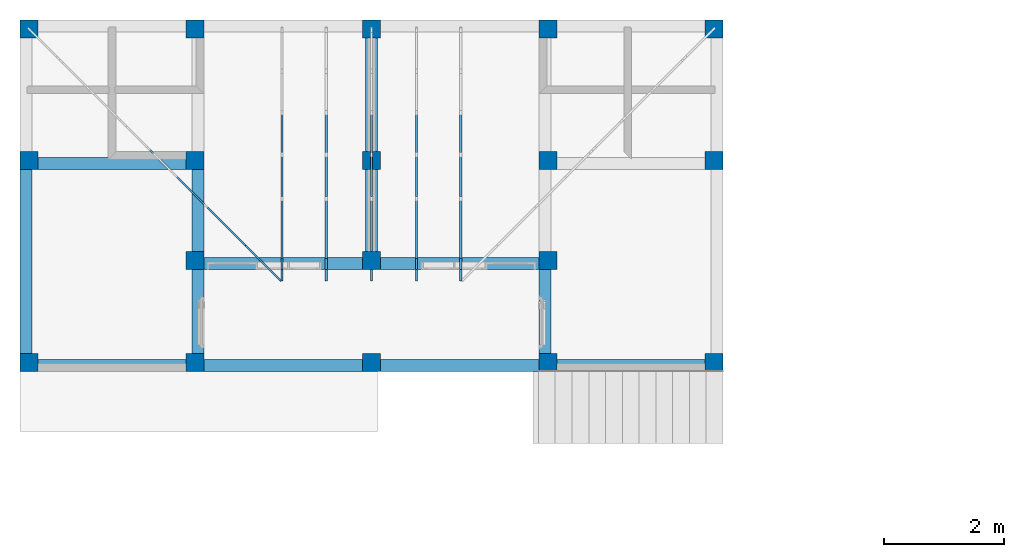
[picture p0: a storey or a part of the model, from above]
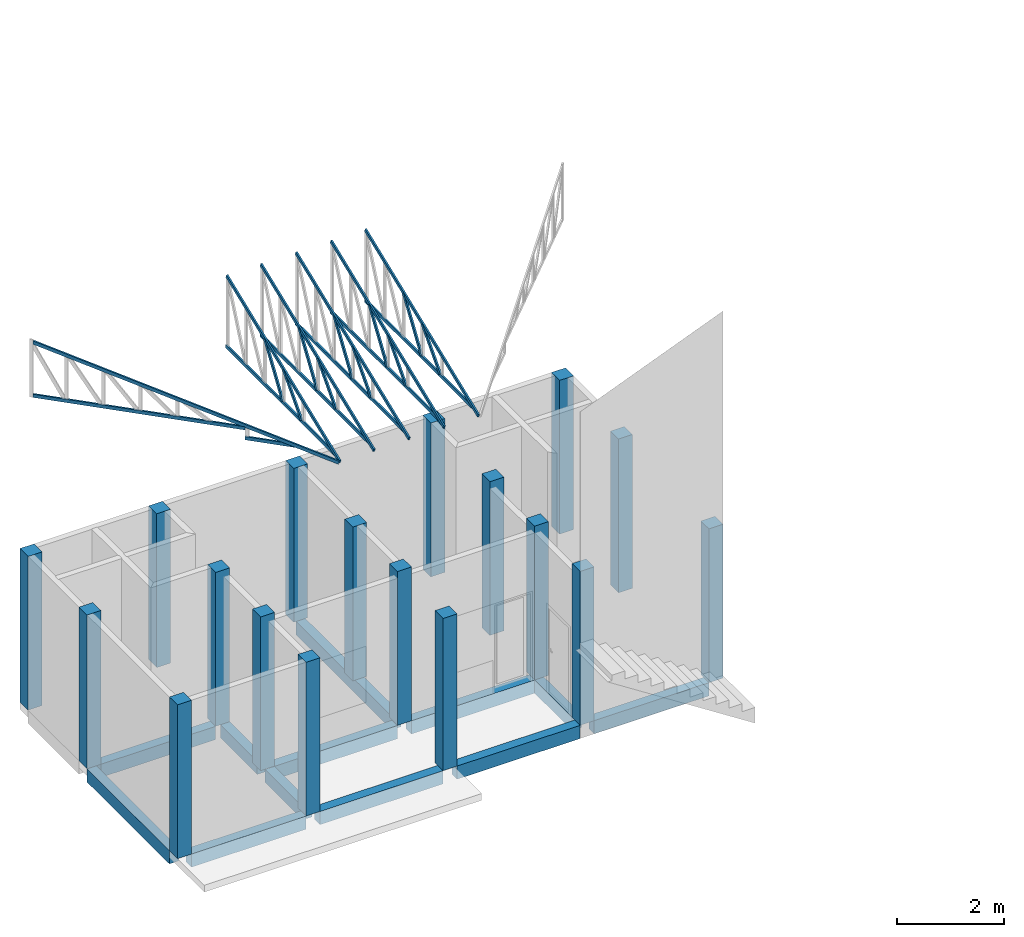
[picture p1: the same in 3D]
Properties of the parts of a building model (IFC4X3_ADD2)

# File
Description: ViewDefinition[DesignTransferView]
File name: kost-IFC4X3.ifc
Time: 2025-10-08T06:04:25+08:00
Written by: IfcOpenShell 0.8.4-alpha251007
Made in: Bonsai 0.8.4-alpha251007-bd0cfa5
Authorization: Nobody

# IfcProject, My Project
Document: BBIM_Cost_Documents; Beam; LANTAI 2 PLAN; UNTITLED; SOUTH ELEVATION; Beam LT2; ATAS PLAN; RANGKA ATAP; ORTHOGRAPHIC

# IfcAnnotation (11)
Group: LANTAI 1 PLAN
Name | PredefinedType
7 x DIMENSION | DIMENSION
4 x TEXT | TEXT | EPset_Annotation - Newline_At: 0; Reverse_List: no; List_Separator: ,

# IfcAnnotation: DRAWING (9)
PredefinedType: USERDEFINED
EPset_Drawing - HasUnderlay: no; HasLinework: yes; HasAnnotation: yes; GlobalReferencing: yes; Markers: drawings/assets/markers.svg; Symbols: drawings/assets/symbols.svg; Patterns: drawings/assets/patterns.svg; ShadingStyles: drawings/assets/shading_styles.json
Name | Document | TargetView | Scale | HumanScale | Stylesheet | CurrentShadingStyle | BringToFront | Group
LANTAI 1 PLAN | X drawings/Beam.svg | PLAN_VIEW | 1/100 | 1:100 | drawings/assets/default.css | Blender Default | IfcColumn | LANTAI 1 PLAN
LANTAI 2 PLAN | X drawings/LANTAI 2 PLAN.svg | PLAN_VIEW | 1/100 | 1:100 | drawings/assets/default.css | Blender Default | IfcColumn | LANTAI 2 PLAN
LANTAI 1 PLAN-X | X drawings/Beam.svg | PLAN_VIEW | 1/100 | 1:100 | drawings/assets/default.css | Blender Default | IfcColumn | LANTAI 1 PLAN-X
Beam | X drawings/Beam.svg | PLAN_VIEW | 1/100 | 1:100 | drawings/assets/Beam.css | Blender Default | IfcColumn | Beam | EPset_Drawing - Exclude: IfcWall, IfcDoor, IfcSlab
SOUTH ELEVATION | X drawings/SOUTH ELEVATION.svg | ELEVATION_VIEW | 1/100 | 1:100 | drawings/assets/default.css | Technical |  | SOUTH ELEVATION
Beam LT2 | X drawings/Beam LT2.svg | PLAN_VIEW | 1/100 | 1:100 | drawings/assets/default.css | Blender Default | IfcColumn | Beam LT2 | EPset_Drawing - Exclude: IfcElement, !IfcColumn, !IfcBeam
ATAS PLAN | X drawings/ATAS PLAN.svg | PLAN_VIEW | 1/100 | 1:100 | drawings/assets/default.css | Blender Default |  | ATAS PLAN
RANGKA ATAP | X drawings/RANGKA ATAP.svg | PLAN_VIEW | 1/50 | 1:50 | drawings/assets/default.css | Blender Default |  | RANGKA ATAP | EPset_Drawing - Exclude: IfcRoof, IfcWall, IfcDoor, IfcCovering
ORTHOGRAPHIC | X drawings/ORTHOGRAPHIC.svg | MODEL_VIEW | 1/100 | 1:100 | drawings/assets/default.css | Blender Default |  | ORTHOGRAPHIC

# IfcAnnotation: ELEVATION (6)
PredefinedType: USERDEFINED
Name | Group
IfcAnnotation/SOUTH ELEVATION | Beam
IfcAnnotation/SOUTH ELEVATION | LANTAI 2 PLAN
IfcAnnotation/SOUTH ELEVATION | Beam LT2
IfcAnnotation/SOUTH ELEVATION | ATAS PLAN
IfcAnnotation/SOUTH ELEVATION | RANGKA ATAP
IfcAnnotation/SOUTH ELEVATION | LANTAI 1 PLAN

# IfcAnnotation: GRID (105)
PredefinedType: USERDEFINED
Name | Group
4 x A | LANTAI 1 PLAN
2 x B | LANTAI 1 PLAN
D | LANTAI 1 PLAN
01 | LANTAI 1 PLAN
2 x 02 | LANTAI 1 PLAN
3 x 03 | LANTAI 1 PLAN
2 x 04 | LANTAI 1 PLAN
4 x 05 | LANTAI 1 PLAN
2 x A | LANTAI 2 PLAN
2 x B | LANTAI 2 PLAN
3 x C | LANTAI 2 PLAN
3 x 01 | LANTAI 2 PLAN
4 x 02 | LANTAI 2 PLAN
3 x 03 | LANTAI 2 PLAN
04 | LANTAI 2 PLAN
05 | LANTAI 2 PLAN
2 x C | LANTAI 1 PLAN
2 x A | Beam
B | Beam
2 x C | Beam
01 | Beam
02 | Beam
4 x 03 | Beam
04 | Beam
05 | Beam
4 x 03 | SOUTH ELEVATION
01 | SOUTH ELEVATION
02 | SOUTH ELEVATION
05 | SOUTH ELEVATION
2 x A | Beam LT2
B | Beam LT2
2 x C | Beam LT2
01 | Beam LT2
02 | Beam LT2
3 x 03 | Beam LT2
04 | Beam LT2
05 | Beam LT2
3 x C | ATAS PLAN
4 x 03 | ATAS PLAN
2 x A | ATAS PLAN
B | ATAS PLAN
01 | ATAS PLAN
02 | ATAS PLAN
04 | ATAS PLAN
05 | ATAS PLAN
2 x A | RANGKA ATAP
B | RANGKA ATAP
C | RANGKA ATAP
01 | RANGKA ATAP
02 | RANGKA ATAP
2 x 03 | RANGKA ATAP
04 | RANGKA ATAP
05 | RANGKA ATAP
04 | SOUTH ELEVATION
A | ORTHOGRAPHIC
B | ORTHOGRAPHIC
C | ORTHOGRAPHIC
01 | ORTHOGRAPHIC
02 | ORTHOGRAPHIC
03 | ORTHOGRAPHIC
04 | ORTHOGRAPHIC
05 | ORTHOGRAPHIC

# IfcAnnotation: SECTION_LEVEL (5)
PredefinedType: USERDEFINED; Group: SOUTH ELEVATION
Name
IfcBuildingStorey/Lantai 1
IfcBuildingStorey/Lantai 2
IfcBuildingStorey/Riang Blok
IfcBuildingStorey/Pondasi
IfcBuildingStorey/ATAS

# IfcBeam: RB (25)
In: Lantai 2
Type - PredefinedType: BEAM; Material: plester
EPset_Parametric - Engine: Bonsai.DumbProfile
Name | Group
5 x Beam
20 x Beam | TB_LT2

# IfcBeam: TB1 (52)
Type - PredefinedType: BEAM; Material: plester
EPset_Parametric - Engine: Bonsai.DumbProfile
Name | In
22 x Beam | Lantai 1
Beam | Lantai 1 | Group: TB_LT2
3 x Beam | Riang Blok
20 x Beam | Lantai 2 | Group: TB_LT2
5 x Beam | Lantai 2
Beam | Pondasi

# IfcColumn: K1 (35)
Type - PredefinedType: COLUMN; Material: plester
EPset_Parametric - Engine: Bonsai.DumbProfile
Name | In
18 x Column | Lantai 1
17 x Column | Pondasi

# IfcColumn: K2 (17)
In: Lantai 2
Type - PredefinedType: COLUMN; Material: plester
EPset_Parametric - Engine: Bonsai.DumbProfile
Group: K2
Name
16 x Column
Column | BBIM_Boolean - Data: [102000]

# IfcCovering: cat (3)
Type - PredefinedType: CLADDING; Material: plester 1 mm
Type - EPset_Parametric - LayerSetDirection: AXIS2
EPset_Parametric - Engine: Bonsai.DumbLayer2
Name | In | Data
Covering | Lantai 1 | [29553]
Covering | Lantai 2 | [54905]
Covering | Lantai 1 | [54975]

# IfcDoor: 1 (7)
Type - PredefinedType: DOOR
Name | In
6 x Door | Lantai 1
Door | Lantai 2

# IfcDoor: D01 L (2)
Type - PredefinedType: BOOM_BARRIER; OperationType: SINGLE_SWING_LEFT
Type - BBIM_Door - Data: {"door_type": "SINGLE_SWING_LEFT", "overall_height": 2000.0, "overall_width": 850.0000238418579, "lining_properties": {"lining_depth": 50.00000074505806, "lining_thickness": 50.00000074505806, "lining_offset": 0.0, "lining_to_panel_offset_x": 25.00000037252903, "lining_to_panel_offset_y": 25.00000037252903, "transom_thickness": 0.0, "casing_thickness": 75.00000298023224, "casing_depth": 4.999999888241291, "threshold_thickness": 25.00000037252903, "threshold_depth": 100.00000149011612, "threshold_offset": 0.0}, "panel_properties": {"panel_depth": 35.00000014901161, "panel_width_ratio": 1.0}}
OverallHeight: 2000 mm; OverallWidth: 850 mm
Name | In
Door | Lantai 1
Door | Lantai 2

# IfcDoor: D01 R (2)
Type - PredefinedType: DOOR; OperationType: SINGLE_SWING_LEFT
Type - BBIM_Door - Data: {"door_type": "SINGLE_SWING_RIGHT", "overall_height": 2000.0, "overall_width": 850.0000238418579, "lining_properties": {"lining_depth": 50.00000074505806, "lining_thickness": 50.00000074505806, "lining_offset": 0.0, "lining_to_panel_offset_x": 25.00000037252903, "lining_to_panel_offset_y": 25.00000037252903, "transom_thickness": 0.0, "casing_thickness": 75.00000298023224, "casing_depth": 4.999999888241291, "threshold_thickness": 25.00000037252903, "threshold_depth": 100.00000149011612, "threshold_offset": 0.0}, "panel_properties": {"panel_depth": 35.00000014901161, "panel_width_ratio": 1.0}}
OverallHeight: 2000 mm; OverallWidth: 850 mm
Name | In
Door | Lantai 1 | OperationType: SINGLE_SWING_RIGHT
Door | Lantai 2

# IfcDoor: xxxx (5)
Type - PredefinedType: DOOR
Name | In
4 x Door | Lantai 1
Door | Lantai 2 | Material: Kayu

# IfcElementAssembly (23)
Name | In | Index | Name | Aggregate_Index | Group
wally | Lantai 1
KUDA KUDA 2_1 | Riang Blok | 0 | KUDA KUDA 2 | 1 | BBIM_Linked_Aggregate
KK2_0 | Lantai 1 | 0 | KK2 | 0 | BBIM_Linked_Aggregate
KUDA KUDA 2_0 | Riang Blok | 0 | KUDA KUDA 2 | 0 | BBIM_Linked_Aggregate
wall | Lantai 2
KUDA KUDA_1 | Riang Blok | 0 | KUDA KUDA | 1 | BBIM_Linked_Aggregate
KK2_1 | Lantai 1 | 0 | KK2 | 1 | BBIM_Linked_Aggregate
KK1_1 | Lantai 1 | 0 | KK1 | 1 | BBIM_Linked_Aggregate
2 x KK4 | Pondasi | 12 |  |  | BBIM_Linked_Aggregate
2 x KK7 | Pondasi | 11 |  |  | BBIM_Linked_Aggregate
2 x KK9 | Pondasi | 8 |  |  | BBIM_Linked_Aggregate
2 x KK10 | Pondasi | 8 |  |  | BBIM_Linked_Aggregate
KUDA KUDA_0 | Riang Blok | 0 | KUDA KUDA | 0 | BBIM_Linked_Aggregate
KUDA KUDA_2 | Riang Blok | 0 | KUDA KUDA | 2 | BBIM_Linked_Aggregate
KUDA KUDA_3 | Riang Blok | 0 | KUDA KUDA | 3 | BBIM_Linked_Aggregate
KK1_4 | Lantai 1 | 0 | KK1 | 4 | BBIM_Linked_Aggregate
KK1_3 | Lantai 1 | 0 | KK1 | 3 | BBIM_Linked_Aggregate
KK1_2 | Lantai 1 | 0 | KK1 | 2 | BBIM_Linked_Aggregate
KK1_0 | Lantai 1 | 0 | KK1 | 0 | BBIM_Linked_Aggregate

# IfcFooting: Pad Foot 1 (17)
In: Pondasi
Type - PredefinedType: CAISSON_FOUNDATION

# IfcGeographicElement, Plane
In: Lantai 2
PredefinedType: TERRAIN

# IfcGroup: SEARCH (2)
Name | Description
K2 | {"type": "BBIM_Search", "query": "IfcColumn, location=\"Lantai 2\""}
TB_LT2 | {"type": "BBIM_Search", "query": "type=\"TB1\", location=\"Lantai 2\""}

# IfcMember: C75 (201)
Type - PredefinedType: MEMBER; Material: Galvanis
EPset_Parametric - Engine: Bonsai.DumbProfile
Name | In | Index
2 x Member.018 | Riang Blok | 12
Member.019 | Riang Blok | 5
Member.020 | Riang Blok | 6
Member.021 | Riang Blok | 8
Member.022 | Riang Blok | 9
Member.023 | Riang Blok | 4
Member.024 | Riang Blok | 2
2 x Member | Riang Blok | 11
2 x Member | Riang Blok | 10
Member | Lantai 1 | 6
Member | Lantai 1 | 11
Member | Lantai 1 | 8
Member | Lantai 1 | 4
Member | Lantai 1 | 10
Member | Lantai 1 | 9
Member | Lantai 1 | 5
Member | Lantai 1 | 2
Member | Lantai 1 | 14
Member | Lantai 1 | 12
Member | Lantai 1 | 7
Member | Lantai 1 | 3
Member | Lantai 1 | 1
Member | Lantai 1 | 13
Member.015 | Riang Blok | 5
Member.023 | Riang Blok | 6
Member.025 | Riang Blok | 8
Member.026 | Riang Blok | 9
Member.027 | Riang Blok | 2
Member.028 | Riang Blok | 4
Member | Riang Blok | 7
Member | Riang Blok | 1
2 x Member | Riang Blok | 2
Member | Riang Blok | 3
Member | Riang Blok | 8
Member | Riang Blok | 5
Member | Riang Blok | 4
Member | Riang Blok | 6
Member.030 | Lantai 1 | 6
Member.035 | Lantai 1 | 2
Member.038 | Lantai 1 | 12
Member.039 | Lantai 1 | 3
Member.041 | Lantai 1 | 11
Member.043 | Lantai 1 | 14
Member.045 | Lantai 1 | 10
Member.046 | Lantai 1 | 5
Member.047 | Lantai 1 | 8
Member.048 | Lantai 1 | 9
Member.049 | Lantai 1 | 7
Member.050 | Lantai 1 | 13
Member.051 | Lantai 1 | 4
Member.053 | Lantai 1 | 1
4 x Member.057 | Pondasi | 5
4 x Member.054 | Pondasi | 11
4 x Member.060 | Pondasi | 2
2 x Member.056 | Pondasi | 10
4 x Member.052 | Pondasi | 1
2 x Member.064 | Pondasi | 8
4 x Member.061 | Pondasi | 7
2 x Member.058 | Pondasi | 3
4 x Member.065 | Pondasi | 4
4 x Member.063 | Pondasi | 9
2 x Member.058 | Pondasi | 12
Member.059 | Lantai 1 | 11
Member.062 | Lantai 1 | 10
Member.066 | Lantai 1 | 8
Member.067 | Lantai 1 | 4
Member.068 | Lantai 1 | 12
Member.070 | Lantai 1 | 1
Member.072 | Lantai 1 | 2
Member.074 | Lantai 1 | 5
Member.079 | Lantai 1 | 7
Member.098 | Lantai 1 | 3
Member.144 | Lantai 1 | 9
2 x Member.061 | Pondasi | 12
4 x Member | Pondasi | 1
4 x Member | Pondasi | 6
4 x Member | Pondasi | 7
4 x Member | Pondasi | 2
4 x Member | Pondasi | 3
4 x Member | Pondasi | 8
4 x Member | Pondasi | 5
2 x Member | Pondasi | 4
Member.001 | Riang Blok | 1
Member.002 | Riang Blok | 3
Member.003 | Riang Blok | 5
Member.004 | Riang Blok | 7
Member.005 | Riang Blok | 8
Member.006 | Riang Blok | 4
Member.007 | Riang Blok | 6
Member.015 | Riang Blok | 1
Member.113 | Riang Blok | 3
Member.114 | Riang Blok | 5
Member.115 | Riang Blok | 2
Member.116 | Riang Blok | 7
Member.117 | Riang Blok | 8
Member.118 | Riang Blok | 4
Member.120 | Riang Blok | 6
Member.175 | Riang Blok | 1
Member.180 | Riang Blok | 3
Member.177 | Riang Blok | 5
Member.176 | Riang Blok | 2
Member.153 | Riang Blok | 7
Member.179 | Riang Blok | 8
Member.178 | Riang Blok | 4
Member.181 | Riang Blok | 6
Member.069 | Lantai 1 | 11
Member.073 | Lantai 1 | 5
Member.075 | Lantai 1 | 7
Member.076 | Lantai 1 | 2
Member.078 | Lantai 1 | 1
Member.080 | Lantai 1 | 12
Member.146 | Lantai 1 | 9
Member.081 | Lantai 1 | 3
Member.082 | Lantai 1 | 10
Member.083 | Lantai 1 | 4
Member.088 | Lantai 1 | 8
Member.071 | Lantai 1 | 11
Member.077 | Lantai 1 | 5
Member.084 | Lantai 1 | 7
Member.094 | Lantai 1 | 2
Member.097 | Lantai 1 | 1
Member.099 | Lantai 1 | 12
Member.150 | Lantai 1 | 9
Member.100 | Lantai 1 | 3
Member.101 | Lantai 1 | 10
Member.102 | Lantai 1 | 4
Member.104 | Lantai 1 | 8
Member.052 | Lantai 1 | 11
Member.054 | Lantai 1 | 5
Member.056 | Lantai 1 | 7
Member.057 | Lantai 1 | 2
Member.058 | Lantai 1 | 1
Member.060 | Lantai 1 | 12
Member.145 | Lantai 1 | 9
Member.061 | Lantai 1 | 3
Member.063 | Lantai 1 | 10
Member.064 | Lantai 1 | 4
Member.065 | Lantai 1 | 8
Member.008 | Lantai 1 | 11
Member.009 | Lantai 1 | 5
Member.010 | Lantai 1 | 7
Member.011 | Lantai 1 | 2
Member.013 | Lantai 1 | 1
Member.014 | Lantai 1 | 12
Member.132 | Lantai 1 | 9
Member.016 | Lantai 1 | 3
Member.026 | Lantai 1 | 10
Member.028 | Lantai 1 | 4
Member.044 | Lantai 1 | 8

# IfcMember: Reng (30)
In: ATAS
Type - PredefinedType: MEMBER; Material: plester
EPset_Parametric - Engine: Bonsai.DumbProfile
Name
28 x Member
Member | BBIM_Array - Data: [{"children": ["3TvIhc9pfEYuKzHwPHs3dD", "1FkifGy8PCqe1wJ2PLcNma", "0JiBCoxiD9FQeGv4SQLU4b", "37NurKf7v6COC$roMtjej7", "1hNxyy2W5BxftOFLhMVoLM", "2d_yeNB49Fwv88I5m3Hhu2", "3mj$gqNiH6FhJAfE9GkfX5", "1LEWYU_zr84uYP9d89TB4w", "25mhQu0q57tB$gTcjAs48T"], "count": 10, "x": 500.0, "y": 0.0, "z": 0.0, "use_local_space": true, "sync_children": false, "method": "OFFSET"}]
Member | BBIM_Array - Data: [{"children": ["27wKmbwl927fDuq3ePcf0u", "2w2DD_xSz1kxnGiBpZHNbY", "3i8X3KU3f7VAfgsTxf8EOo", "1ojcabggjFTuUK3On6n6kV", "0v$6kMiXT3$PgFXc8uNjWi", "2kX9mfaRnDNO55V7iZQUwI", "0$bd0SPa56YwnOfVy2RVt6", "3ggYDv4LPA8fmtPO4Tfh8Y", "39PcPv2EL7OhlvTmPJ$4$f"], "count": 10, "x": -500.0, "y": 0.0, "z": 0.0, "use_local_space": true, "sync_children": false, "method": "OFFSET"}]

# IfcOpeningElement (18)
PredefinedType: OPENING
Name | In
10 x Opening | Lantai 1
4 x Opening | Lantai 2
3 x Opening
Opening | Pondasi

# IfcRoof: Roof
In: Riang Blok
Type - PredefinedType: GABLE_ROOF; Material: plester 100 mm
Type - EPset_Parametric - LayerSetDirection: AXIS3
EPset_Parametric - Engine: Bonsai.DumbLayer3

# IfcSlab: concrete slab (3)
Type - PredefinedType: FLOOR; Material: concrete 120 mm, keramik 35 mm
Type - EPset_Parametric - LayerSetDirection: AXIS3
EPset_Parametric - Engine: Bonsai.DumbLayer3
Name | In
Slab | Lantai 1
2 x Slab | Lantai 2

# IfcStairFlight: stair, StairFlight
In: Lantai 1
Type - PredefinedType: STRAIGHT
Type - BBIM_Stair - Data: {"stair_type": "CONCRETE", "width": 1200.0000476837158, "height": 1990.0000095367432, "number_of_treads": 10, "tread_run": 280.0000309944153, "nosing_length": 0.0, "nosing_depth": 0.0, "base_slab_depth": 250.0, "top_slab_depth": 120.00000476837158, "has_top_nib": true, "tread_depth": 150.00000596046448, "custom_first_last_tread_run": [0.0, 0.0]}
Type - Pset_StairFlightCommon - NumberOfRiser: 11; NumberOfTreads: 10; RiserHeight: 180.909 mm; TreadLength: 150 mm; NosingLength: 0 mm
NumberOfRisers: 11; NumberOfTreads: 10; RiserHeight: 180.909 mm; TreadLength: 150 mm

# IfcStairFlight: stair 2, StairFlight
In: Lantai 2
Type - PredefinedType: SPIRAL
Type - BBIM_Stair - Data: {"stair_type": "CONCRETE", "width": 1200.0000476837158, "height": 1750.0001192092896, "number_of_treads": 9, "tread_run": 280.0000011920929, "nosing_length": 0.0, "nosing_depth": 0.0, "base_slab_depth": 120.00000476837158, "top_slab_depth": 120.00000476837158, "has_top_nib": true, "tread_depth": 120.00000476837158, "custom_first_last_tread_run": [0.0, 0.0]}
Type - Pset_StairFlightCommon - NumberOfRiser: 10; NumberOfTreads: 9; RiserHeight: 175 mm; TreadLength: 120 mm; NosingLength: 0 mm
NumberOfRisers: 10; NumberOfTreads: 9; RiserHeight: 175 mm; TreadLength: 120 mm; PredefinedType: STRAIGHT

# IfcWall: WALL-130 (40)
Type - Description: dgdfggdfg dffgsdfgs; PredefinedType: SOLIDWALL; Material: plester 15 mm, brick 100 mm, plester 15 mm
Type - EPset_Parametric - LayerSetDirection: AXIS2
EPset_Parametric - Engine: Bonsai.DumbLayer2
Name | In
19 x Wall | Lantai 1
2 x Wall | Riang Blok
15 x Wall | Lantai 2
Wall | Lantai 2 | BBIM_Boolean - Data: [49722, 11903]
Wall | Lantai 2 | BBIM_Boolean - Data: [11943]
Wall | Lantai 2 | BBIM_Boolean - Data: [47097, 47069]
Wall | Pondasi

# IfcWindow: W02 (2)
Type - PredefinedType: WINDOW
Name | In
Window | Pondasi
Window | Lantai 1

# IfcBeamType, no part of this type: K2
PredefinedType: BEAM; Material: plester

# IfcRoofType, no part of this type: Unnamed
PredefinedType: HIP_ROOF
BBIM_Roof - Data: {"roof_type": "HIP/GABLE ROOF", "generation_method": "HEIGHT", "roof_thickness": 100.00000149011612, "rafter_edge_angle": 1.5707963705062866, "height": 1680.0000667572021, "path_data": {"edges": [[0, 1], [2, 3], [7, 4], [5, 6], [6, 2], [1, 5], [4, 0], [3, 7]], "verts": [[-4432.734375, 4236.95068359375, 0.0], [15518.490234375, 4236.95068359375, 0.0], [7044.2451171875, -4237.49951171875, 0.0], [4041.508544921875, -4237.49951171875, 0.0], [-4432.734375, -5607.4990234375, 0.0], [15518.490234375, -5607.4990234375, 0.0], [7044.2451171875, -5607.4990234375, 0.0], [4041.508544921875, -5607.4990234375, 0.0]], "gable_roof_angles": [1.5707963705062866, 0.0, 1.5707963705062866, 1.5707963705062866, 0.0, 0.0, 0.0, 0.0]}}

# IfcStairType, no part of this type: stair
PredefinedType: STRAIGHT_RUN_STAIR
BBIM_Stair - Data: {"stair_type": "CONCRETE", "width": 1200.0000476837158, "height": 1000.0, "number_of_treads": 6, "tread_run": 300.00001192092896, "nosing_length": 0.0, "nosing_depth": 0.0, "base_slab_depth": 250.0, "top_slab_depth": 250.0, "has_top_nib": true, "tread_depth": 250.0, "custom_first_last_tread_run": [0.0, 0.0]}
Pset_StairFlightCommon - NumberOfRiser: 7; NumberOfTreads: 6; RiserHeight: 142.857 mm; TreadLength: 250 mm; NosingLength: 0 mm
